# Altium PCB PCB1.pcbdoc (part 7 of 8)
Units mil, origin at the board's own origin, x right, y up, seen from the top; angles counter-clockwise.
Board outline 5129 x 4161 mil, 8 copper layers (Top Layer, GND1, 内层2, VCC, 内层4, Inner5, GND2, Bottom Layer); 498 components, 453 nets, 2574 pads, 1361 vias.

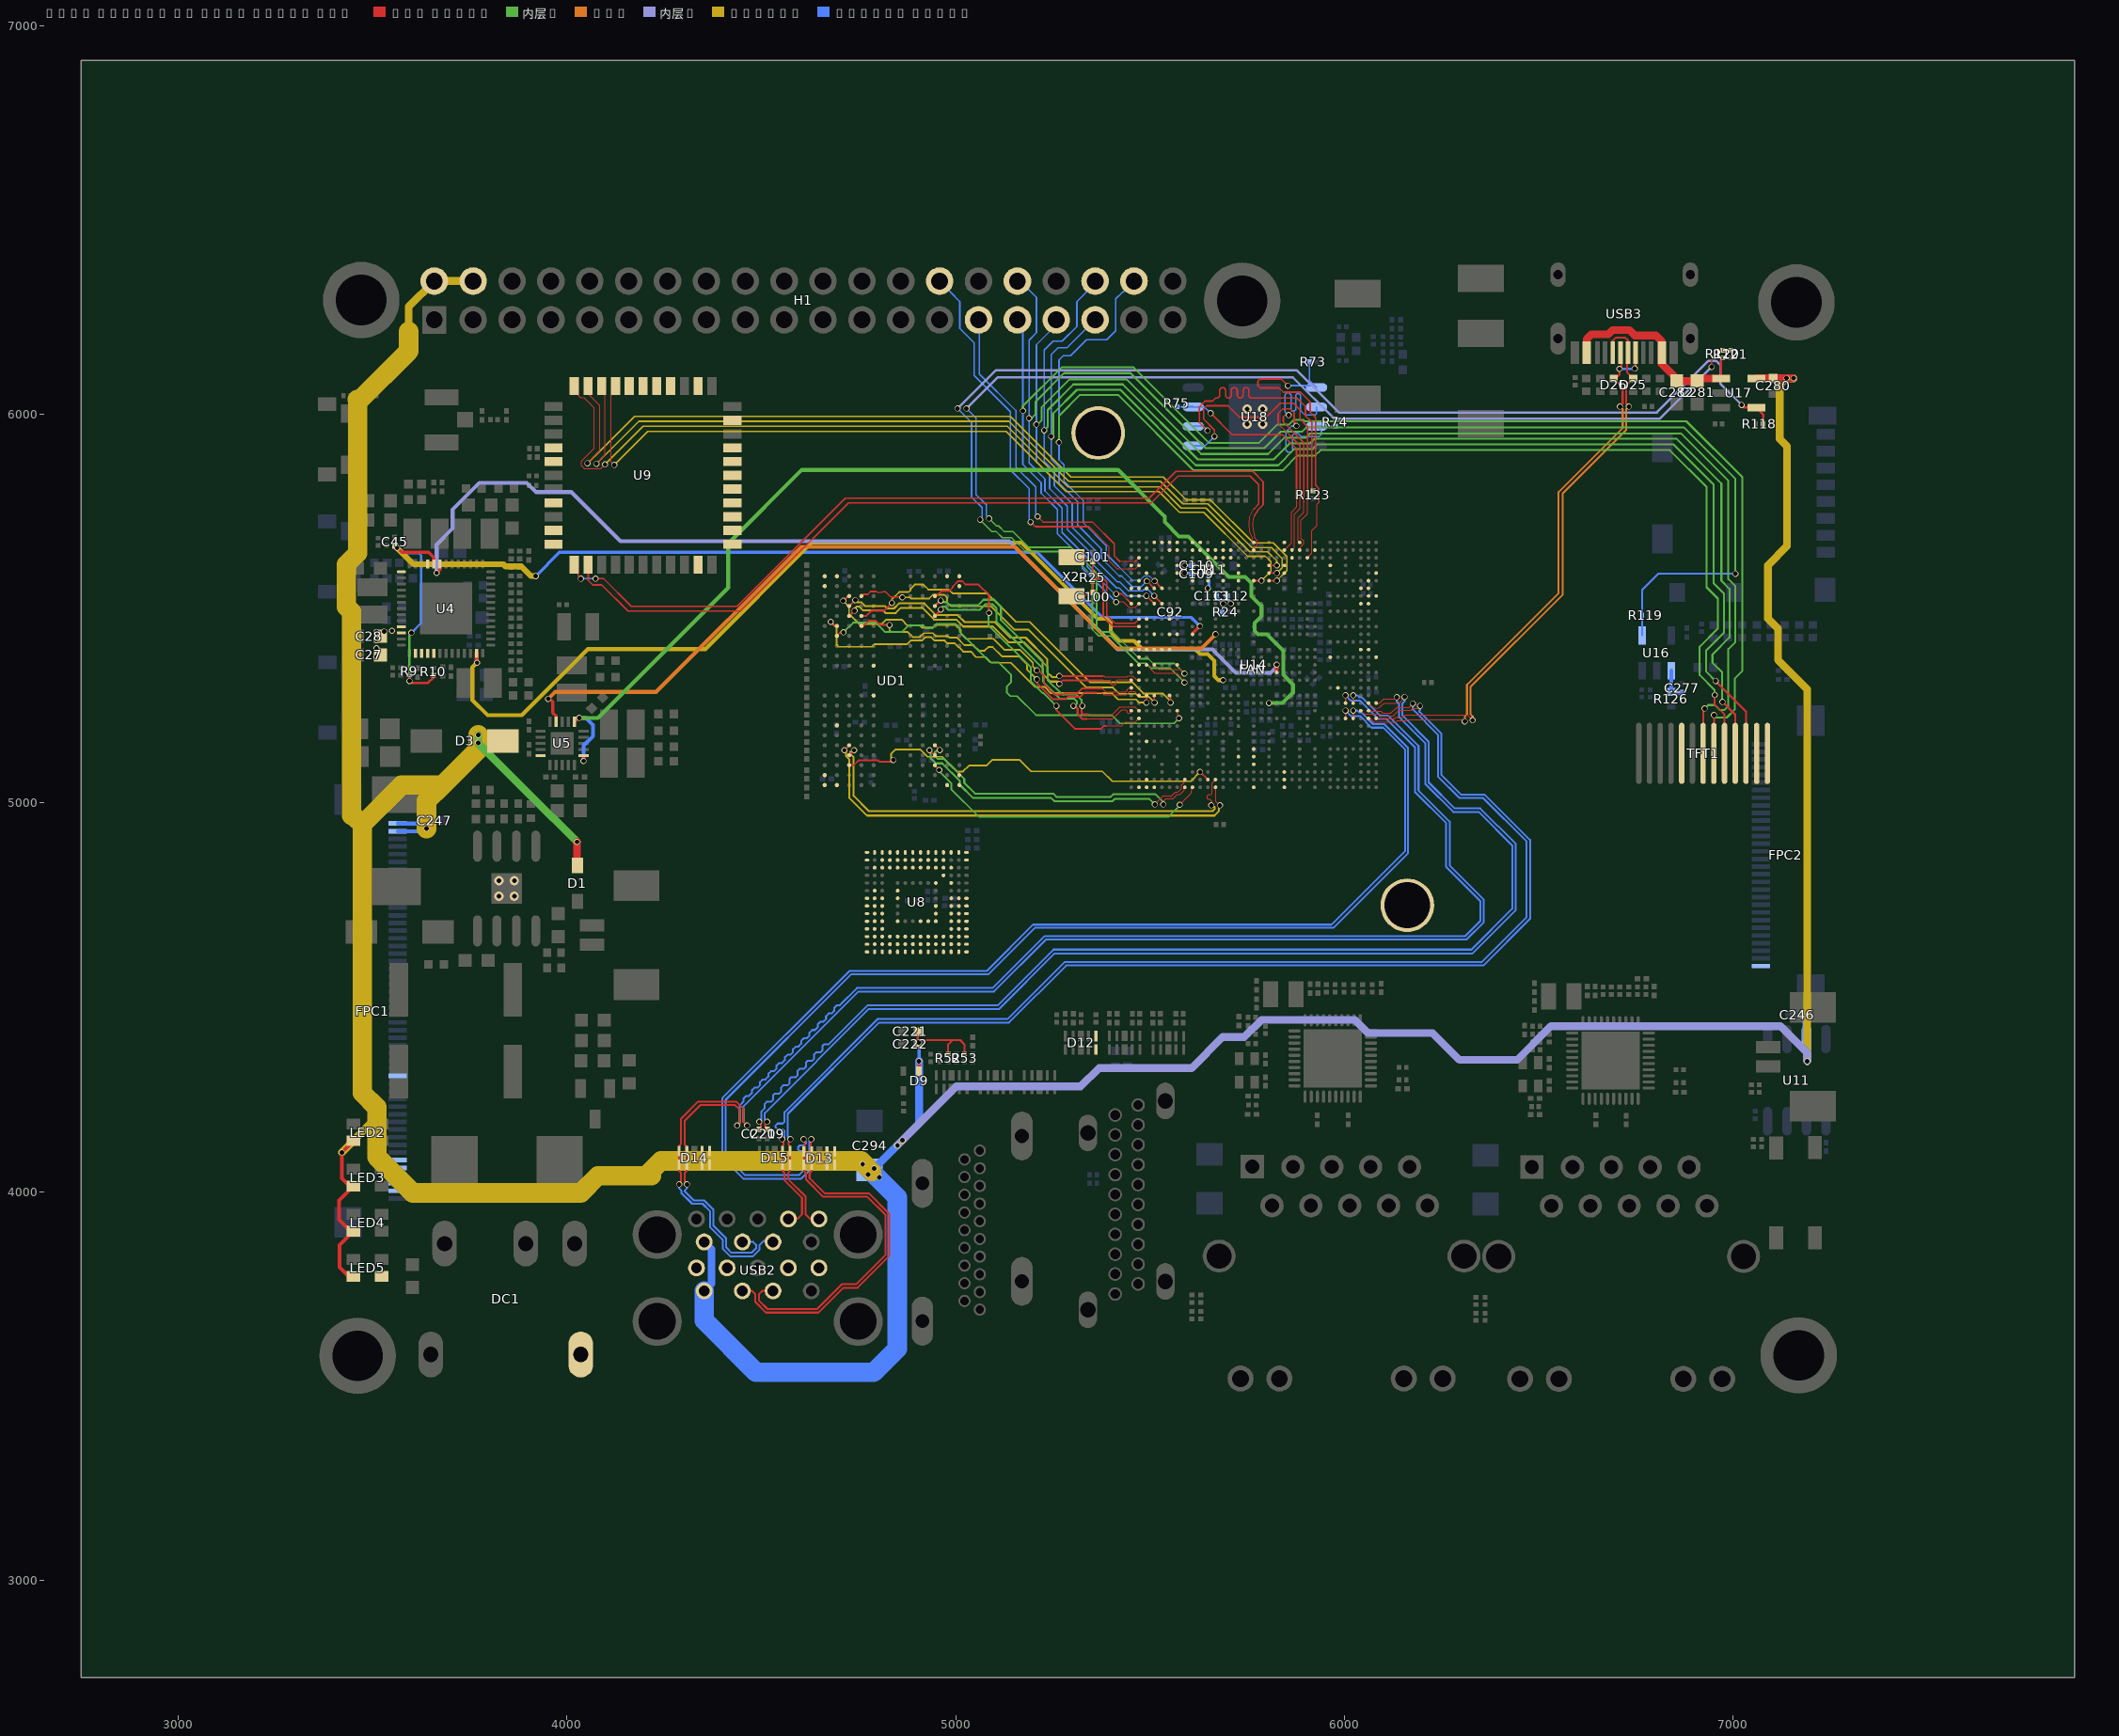
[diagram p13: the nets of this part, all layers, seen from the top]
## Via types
v1: diameter 15.7, hole 11.8, Top Layer to Bottom Layer, 570 vias
v2: diameter 15.75, hole 11.8, Top Layer to Bottom Layer, 504 vias
v3: diameter 15.75, hole 11.81, Top Layer to Bottom Layer, 279 vias
v4: diameter 24, hole 12, Top Layer to Bottom Layer, 8 vias

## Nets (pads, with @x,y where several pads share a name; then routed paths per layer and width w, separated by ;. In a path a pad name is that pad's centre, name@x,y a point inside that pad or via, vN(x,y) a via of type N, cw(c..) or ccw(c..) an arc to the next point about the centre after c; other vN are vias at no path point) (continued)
SDQ28: U14.AM21 UD1.U9 | length 856.7
  Top Layer w3: 5362.25,5283.97 5376.92,5283.97 5382.89,5278 5438.76,5278 5447.18,5286.42 5461.55,5286.42 U14.AM21@5471.37,5276.6
  Top Layer w4.5: UD1.U9@4757.66,5455.99 4763.94,5455.99 4776.92,5468.97 4794.92,5468.97 4805.92,5457.97 v3(4829.92,5457.97) ; v3(5209.02,5318.07) 5209.02,5308.87 5250.92,5266.97 5282.92,5266.97 5288.92,5272.97 5319.92,5272.97 5330.92,5283.97 5362.25,5283.97
  Inner5 w4.5: v3(4829.92,5457.97) 4829.92,5444.47 4834.42,5439.97 4876.92,5439.97 4889.92,5426.97 4907.92,5426.97 4917.92,5436.97 4941.92,5436.97 4949.92,5428.97 4980.92,5428.97 4983.92,5425.97 5002.92,5425.97 5022.92,5405.97 5045.6,5405.97 5059.6,5391.97 5074.92,5391.97 5083.92,5400.97 5095.58,5400.97 5119.08,5377.47 5162.42,5377.47 5183.92,5355.97 5183.92,5342.63 5208.48,5318.07 v3(5209.02,5318.07)
SDQ29: U14.AL21 UD1.U11 | length 983.1
  Top Layer w4.5: v3(4678.84,5465.97) 4688.82,5455.99 UD1.U11@4694.67,5455.99 ; v3(5491.05,5258.43) U14.AL21@5491.05,5276.59
  Inner5 w4.5: v3(4678.84,5465.97) 4693.92,5450.89 4693.92,5406.47 4698.42,5401.97 4784.92,5401.97 4791.92,5408.97 4875.92,5408.97 4884.92,5417.97 4913.97,5417.97 4923,5427 4936.89,5427 4945.92,5417.97 4971.92,5417.97 4978.92,5410.97 4997.92,5410.97 5019.42,5389.47 5038.76,5389.47 5052.76,5375.47 5077.42,5375.47 5091.92,5360.97 5141.92,5360.97 5203.91,5298.98 5228.91,5298.98 5245.42,5282.47 5402.42,5282.47 5418.42,5266.47 5464.42,5266.47 5472.46,5258.43 v3(5491.05,5258.43)
SDQ30: U14.AK21 UD1.Y9 | length 912.8
  Top Layer w4: UD1.Y9@4757.66,5532.76 4761.89,5537 4774,5537 4781,5544 4796,5544 4803,5541 4818.89,5544 4832.92,5529.97 4861.92,5529.97 v3(4862.92,5528.97) ; U14.AK21@5510.73,5276.59 5510.73,5259.57 v3(5511.96,5258.34)
  Inner5 w4.5: v3(4862.92,5528.97) 4881.92,5528.97 4884.92,5525.97 4931.92,5525.97 4941.92,5535.97 4970.92,5535.97 4977.92,5528.97 4977.92,5515.97 4987.92,5505.97 5091.53,5505.97 5151.53,5445.97 5187.56,5445.97 5336.56,5296.97 5404.92,5296.97 5420.92,5280.97 5463.92,5280.97 5471.89,5273 5497.3,5273 v3(5511.96,5258.34)
SDQ31: U14.AH21 UD1.V9 | length 979.8
  Top Layer w4.5: UD1.V9@4757.66,5481.58 4770.54,5481.58 4783.72,5494.76 4816.71,5494.76 4835.92,5513.97 v3(4835.92,5514.97) ; v3(5552.96,5258.34) U14.AH21@5552.96,5273.75
  Inner5 w4.5: v3(4835.92,5514.97) 4835.92,5523.97 4854.92,5542.97 4879.42,5542.97 4883.92,5547.47 4883.92,5550.97 4894.92,5561.97 4916.91,5561.97 4929.91,5548.97 4982.92,5548.97 4992.92,5538.97 5081.87,5538.97 5154.87,5465.97 5190.9,5465.97 5345.9,5310.97 5453.92,5310.97 5482.89,5282 5532.89,5282 5552.96,5261.93 v3(5552.96,5258.34)
SDQM0: U14.AE33 UD1.C3 | length 767.8
  Top Layer w3: v3(5576.61,4995.51) 5605.84,5024.74 5607.28,5033.54 U14.AE33@5608.9,5040.65
  Top Layer w4.5: UD1.C3@4946.64,5097.72 4957.92,5086.44 v3(4957.92,5084.97)
  内层2 w4.5: v3(4957.92,5084.97) 4957.92,5081.97 4988.92,5050.97 4988.92,5035.97 5060.17,4964.72 5547.65,4964.72 5576.44,4993.51 5576.44,4995.34 v3(5576.61,4995.51)
SDQM1: U14.AC32 UD1.C10 | length 1036.8
  Top Layer w4.5: UD1.C10@4726.16,5097.72 4738.67,5097.72 4750.92,5109.97 4800.92,5109.97 4804.92,5105.97 4834.92,5105.97 v3(4839.92,5110.97) ; v3(5628.92,5079.97) 5648.54,5060.35 U14.AC32@5648.54,5060.06
  Inner5 w4.5: v3(4839.92,5110.97) 4833.92,5116.97 4833.92,5125.97 4845.92,5137.97 4908.92,5137.97 4927.92,5118.97 4965.92,5118.97 5003.92,5080.97 5018.92,5080.97 5034.34,5096.39 5079.34,5096.39 5093.92,5110.97 5164.92,5110.97 5194.42,5081.47 5377.42,5081.47 5402.92,5055.97 5604.92,5055.97 v3(5628.92,5079.97)
SDQM2: U14.AM24 UD1.Y3 | length 785.1
  Top Layer w3: 5386.92,5197.97 5425.92,5197.97 5435.43,5207.49 5461.31,5207.49 U14.AM24@5471.37,5217.54
  Top Layer w4.5: UD1.Y3@4946.64,5532.76 4950.71,5532.76 4962.92,5544.97 4982.97,5544.97 4993,5555 4993,5557.45 5006.55,5571 5016.89,5571 5025.92,5561.97 5058.92,5561.97 5085.92,5534.97 v3(5085.92,5488.97) ; v3(5258.92,5249.97) 5258.92,5238.53 5306.48,5190.97 5373.92,5190.97 5380.92,5197.97 5386.92,5197.97
  内层2 w4.5: v3(5085.92,5488.97) 5084.92,5487.97 5084.92,5458.02 5086.92,5456.02 5086.92,5455.65 5193.92,5348.65 5193.92,5312.31 5223.26,5282.97 5225.92,5282.97 v3(5258.92,5249.97)
SDQM3: U14.AN20 UD1.Y10 | length 923.7
  Top Layer w3: 5376.92,5295.24 5386.16,5286 5437.15,5286 5447.44,5296.28 U14.AN20@5451.69,5296.28
  Top Layer w4.5: v3(4710.92,5519.97) 4723.71,5532.76 UD1.Y10@4726.16,5532.76 ; v3(5208.92,5340.97) 5212.92,5340.97 5227.92,5325.97 5227.92,5305.97 5254.92,5278.97 5276.92,5278.97 5279.92,5281.97 5312.92,5281.97 5326.19,5295.24 5376.92,5295.24
  Inner5 w4.5: v3(4710.92,5519.97) 4725.92,5504.97 4725.92,5486.97 4751.92,5460.97 4810.92,5460.97 4821.92,5471.97 4861.03,5471.97 4876.03,5456.97 4907.92,5456.97 4913.92,5450.97 4941.92,5450.97 4948.92,5457.97 4999.92,5457.97 5013.92,5443.97 5013.92,5435.97 5027.17,5422.72 5097.17,5422.72 5125.92,5393.97 5165.92,5393.97 5198.92,5360.97 5198.92,5350.97 v3(5208.92,5340.97)
SDQS0N: U14.AF33 UD1.E3 | length 777.5
  Top Layer w3: v3(5534.44,4996.51) 5534.44,5004.49 5539.92,5009.97 5558.17,5009.97 5569.17,5020.97 5576.24,5020.97 5587.66,5032.39 5587.66,5038.56 U14.AF33@5589.48,5040.38
  Top Layer w3.8: UD1.E3@4946.64,5148.9 v3(4959.44,5136.1)
  内层2 w5: v3(4959.44,5136.1) 4952.41,5136.08 4947.42,5131.05 4947.42,5120.5 4954.48,5113.47 4970.7,5113.47 5022.42,5061.75 5022.42,5051.74 5049.94,5024.22 5250.75,5024.22 5259,5015.97 5398.91,5015.97 5405.41,5022.47 5514.59,5022.47 5534.44,5002.62 v3(5534.44,4996.51)
SDQS0P: U14.AF32 UD1.D3 | length 789.5
  Top Layer w3: v3(5512.44,4996.51) 5532.92,5017 5555,5017 5566,5028 5571.94,5028 5579.92,5035.97 5579.92,5044.97 5589.48,5054.53 U14.AF32@5589.48,5060.06
  Top Layer w5: v3(4932.92,5135.97) 4945.58,5123.31 UD1.D3@4946.64,5123.31
  内层2 w5: v3(4932.92,5135.97) 4935.89,5133.02 4935.92,5115.72 4949.73,5101.97 4965.93,5101.97 5010.92,5056.98 5010.92,5046.97 5045.17,5012.72 5245.98,5012.72 5254.23,5004.47 5403.68,5004.47 5410.18,5010.97 5497.98,5010.97 v3(5512.44,4996.51)
SDQS1N: U14.AB33 UD1.E10 | length 1187.6
  Top Layer w3: U14.AB33@5668.22,5040.38 5668.22,5005.67 v3(5679.92,4993.97)
  Top Layer w5: v3(4713.92,5135.97) 4726.16,5148.21 UD1.E10@4726.16,5148.9
  Inner5 w5: v3(4713.92,5135.97) 4713.92,5135.85 4717.9,5131.87 4717.9,5120.99 4726.42,5112.47 4726.42,5013.47 4772.17,4967.72 5666.18,4967.72 5677.92,4979.46 5677.92,4991.97 v3(5679.92,4993.97)
SDQS1P: U14.AB32 UD1.D10 | length 1194.4
  Top Layer w3: v3(5657.92,4993.97) 5657.92,4998.97 5658.42,4999.47 5658.42,5005.66 5655.42,5008.66 5650.06,5008.66 5646.18,5012.54 5646.18,5016.79 5650.05,5020.66 5655.42,5020.66 5658.42,5023.66 ; 5658.6,5023.82 5658.7,5036.87 5658.36,5050.2 U14.AB32@5668.22,5060.06
  Top Layer w5: UD1.D10@4726.26,5123.31 v3(4738.92,5135.97)
  Inner5 w5: v3(4738.92,5135.97) 4734.42,5135.97 4729.4,5130.95 4729.4,5125.76 4737.92,5117.24 4737.92,5018.24 4776.94,4979.22 5661.41,4979.22 5666.42,4984.23 5666.42,4988.97 5661.42,4993.97 v3(5657.92,4993.97)
SDQS2N: U14.AN23 UD1.V3 | length 741.1
  Top Layer w3: 5337.29,5216.04 5402.98,5216.03 5426.04,5239.09 5438.43,5239.09 5441.43,5236.09 5441.43,5232.72 5444.44,5229.71 5448.68,5229.71 5451.69,5232.72 U14.AN23@5451.69,5237.23
  Top Layer w5: UD1.V3@4946.64,5481.58 4961.92,5496.86 v3(4961.92,5497.97) ; v3(5302.92,5249.97) 5306.92,5249.97 5313.92,5242.97 5313.92,5228.82 5326.7,5216.04 5337.29,5216.04
  内层2 w5: v3(4961.92,5497.97) 4961.92,5500.47 4966.92,5505.47 4973.15,5505.47 4981.65,5496.97 5061.91,5496.97 5076.41,5511.47 5094.43,5511.47 5105.17,5500.73 5105.17,5465.71 5225.42,5345.46 5225.42,5311.41 5268.86,5267.97 5305.41,5267.97 5312.42,5260.96 5312.42,5255.47 5306.92,5249.97 v3(5302.92,5249.97)
SDQS2P: U14.AM23 UD1.W3 | length 740.4
  Top Layer w3: 5339.59,5228.05 5343.84,5228.05 5347.86,5224.03 5399.66,5224.03 5422.72,5247.09 5461.55,5247.05 U14.AM23@5471.37,5237.23
  Top Layer w5: UD1.W3@4946.64,5507.17 4960.05,5520.58 4961.53,5520.58 v3(4961.92,5520.97) ; v3(5325.92,5249.97) 5323.92,5247.97 5323.92,5232.97 5328.92,5227.97 5339.51,5227.97 5339.59,5228.05
  内层2 w5: v3(4961.92,5520.97) 4965.92,5516.97 4977.92,5516.97 4986.42,5508.47 5057.14,5508.47 5071.64,5522.97 5099.2,5522.97 5116.67,5505.5 5116.67,5470.48 5236.92,5350.23 5236.92,5316.18 5273.63,5279.47 5310.18,5279.47 5323.92,5265.73 5323.92,5251.97 v3(5325.92,5249.97)
SDQS3N: U14.AN19 UD1.V10 | length 873.1
  Top Layer w3: 5378.21,5315.99 5396.95,5315.97 5399.95,5312.97 5399.95,5306.23 5402.95,5303.23 5408.94,5303.23 5411.95,5306.24 5411.95,5312.97 5414.95,5315.97 U14.AN19@5451.69,5315.97
  Top Layer w5: UD1.V10@4726.16,5481.58 4726.53,5481.58 v3(4739.92,5494.97) ; v3(5267.17,5306.46) 5276.7,5315.99 5378.21,5315.99
  Inner5 w5: v3(4739.92,5494.97) 4739.92,5499.97 4744.92,5504.97 4752.65,5504.97 4762.15,5495.47 4813.16,5495.47 4819.66,5488.97 4846.19,5488.97 4859.19,5501.97 4914.93,5501.97 4944.93,5471.97 5001.92,5471.97 5019.92,5453.97 5095.92,5453.97 5135.92,5413.97 5175.35,5413.97 5223.92,5365.4 5223.92,5331.98 5243.43,5312.47 5260.64,5312.47 5266.65,5306.46 v3(5267.17,5306.46)
SDQS3P: U14.AM19 UD1.W10 | length 870.7
  Top Layer w3: 5378.21,5325.99 5382.36,5325.99 5384.36,5323.99 5440.54,5323.97 5442.36,5325.79 5457.11,5325.79 5466.93,5315.97 U14.AM19@5471.37,5315.97
  Top Layer w5: UD1.W10@4726.16,5507.17 4727.12,5507.17 v3(4741.92,5521.97) ; v3(5266.92,5326.65) 5267.58,5325.99 5378.21,5325.99
  Inner5 w5: v3(4741.92,5521.97) 4747.42,5516.47 4757.42,5516.47 4766.92,5506.97 4817.93,5506.97 4824.43,5500.47 4841.42,5500.47 4854.42,5513.47 4919.7,5513.47 4949.7,5483.47 5005.53,5483.47 5023.53,5465.47 5100.69,5465.47 5140.69,5425.47 5180.12,5425.47 5235.42,5370.17 5235.42,5336.75 5248.2,5323.97 5264.24,5323.97 v3(5266.92,5326.65)
SPI0-CLK: R123.1 U18.6 | length 751.8
  Top Layer w4: v2(5648,5958) 5627,5979 5627,6019 5642,6034 5661,6034 5669,6042 5672.06,6042 ccw(c5672.06,6049.5) 5679.56,6049.5 5679.56,6061.5 cw(c5687.06,6061.5) 5694.56,6061.5 5694.56,6049.5 ccw(c5702.06,6049.5) 5709.56,6049.5 5709.56,6061.5 cw(c5717.06,6061.5) 5724.56,6061.5 5724.56,6049.5 ccw(c5732.06,6049.5) 5739.56,6049.5 5739.56,6061.5 cw(c5747.06,6061.5) 5754.56,6061.5 5754.56,6049.5 ccw(c5762.06,6049.5) 5762.06,6042 5878,6042 5900,6020 5900,5996 5916,5980 5916,5806.51 R123.1@5920,5802.51
  Bottom Layer w4: U18.6@5611.23,5969 5637,5969 v2(5648,5958)
SPI0-CS: R73.1 U14.K3 U18.1 | length 814.8
  Top Layer w3: U14.K3@5904.69,5631.01 5914.96,5641.28 5914.96,5699.52 5928.04,5712.6 5928.04,5767.86 5934,5773.83 5934,5779
  Top Layer w4: v2(5855,6074) 5838,6091 5783,6091 5777.83,6085.83 5777.83,6073.17 5783,6068 5832,6068 5843,6057 5887,6057 5912,6032 5912,6006 5926,5992 5926,5818 5934,5810 5934,5779
  Bottom Layer w4: v2(5855,6074) U18.1@5923.77,6074 ; R73.1@5910.49,6135 5910.49,6087.28 U18.1@5923.77,6074 ; U18.1@5928.77,6069 U18.1@5923.77,6074
SPI0-HOLD: R75.1 U14.N2 U18.7 | length 626.3
  Top Layer w3: U14.N2@5845.59,5650.71 5862.87,5667.99 5862.87,5747.04 5877,5761.17 5877,5782.3
  Top Layer w4: v2(5656,6003) 5711,5948 5840.04,5948 5877,5911.04 5877,5782.3
  Bottom Layer w4: R75.1@5569,6019.49 5610.74,6019.49 5611.23,6019 5640,6019 v2(5656,6003)
SPI0-MISO: U14.L1 U18.2 | length 657.2
  Top Layer w3: U14.L1@5884.97,5670.43 5881.01,5674.39 5881,5733 5895.89,5747.89 ; 5896,5747.89 5896,5775
  Top Layer w4: v2(5857,5998) 5847,5998 5843,5994 5843,5980 5896,5927 5896,5775
  Bottom Layer w4: v2(5857,5998) 5856,5998 5847,6007 5847,6050 5852,6055 5858,6055 5863,6050 5863,6011.76 5866.1,6008.66 5871.66,6008.66 5875,6012 5875,6050 5878.5,6053.5 5883.5,6053.5 5887,6050 5887,6010 5899,5998 5925,5998 5928.77,6001.77 U18.2@5928.77,6019
SPI0-MOSI: U14.L2 U18.5 | length 815.6
  Top Layer w3: U14.L2@5884.96,5650.74 5884.96,5656.51 5895.2,5666.75 5895.2,5674.08 5889,5680.16 5889,5728 5905.5,5744.5 5905.5,5777
  Top Layer w4: v2(5666,5943) 5666,5960 5638,5988 5638,6014 5646,6022 5701,6022 5730,5993 5799,5993 5835,6029 5869,6029 5886,6012 5886,5988 5905.5,5968.5 5905.5,5777
  Bottom Layer w4: U18.5@5611.23,5919 5642,5919 v2(5666,5943)
SPI0-WP: R74.1 U14.M2 U18.3 | length 766.8
  Top Layer w3: U14.M2@5865.29,5650.71 5871.43,5656.85 5871.43,5743.25 5886.2,5758.02 5886.2,5782
  Top Layer w4: v2(5877,5970) 5871,5976 5871,6004 5861,6014 5842,6014 5830,6002 5830,5976 5886.2,5919.8 5886.2,5782
  Bottom Layer w4: v2(5877,5970) 5865,5970 5850,5955 5850,5908 5855,5903 5862.77,5903 5867,5907.23 5867,5947 5872,5952 5880,5952 5889,5943 5935,5943 5941,5949 5941,5956.77 5928.77,5969 5975.51,5969 R74.1@5977,5970.49
SPI-LCD-BLK: H1.32 R119.2 U14.AN9 U16.4 | length 3640.4
  Top Layer w4: v1(5413,5538) 5426.96,5538 U14.AN9@5452.01,5512.95
  内层2 w5: v1(5189,5990) 5195,5990 5206,6001 5206,6033 5279,6106 5450,6106 5643,5913 5794,5913 5836,5955 5891,5955 5902,5966 6874,5966 7006,5834 v1(7006,5590)
  Bottom Layer w4: H1.32@5159,6343 5166,6343 5208,6301 5208,6210 5189,6191 v1(5189,5990) 5189,5875 5230,5834 5230,5803 5274,5759 5274,5696 5338,5632 5338,5609 5409,5538 v1(5413,5538)
  Bottom Layer w5: U16.4@6766.11,5431.15 6766.11,5548.11 6808,5590 v1(7006,5590)
SPI-LCD-CLK: H1.36 TFT1.4 U14.AJ9 | length 3771.4
  Top Layer w4: v2(5511,5533) 5511,5532.71 U14.AJ9@5530.76,5512.95
  Top Layer w5: v1(6973,5260) 7005.68,5227.32 TFT1.4@7005.68,5127.67
  内层2 w5: v1(5228,5959) 5237,5968 5237,6011 5303,6077 5430,6077 5623,5884 5818,5884 5859,5925 5911,5925 5923,5937 6855,5937 6970,5822 6970,5572 6991,5551 6991,5426 6947,5382 6947,5361 6972,5336 6972,5261 v1(6973,5260)
  Bottom Layer w4: H1.36@5359,6343 5359,6337 5312,6290 5312,6226 5274,6188 5251,6188 5228,6165 v1(5228,5959) 5228,5879 5254,5853 5254,5816 5300,5770 5300,5709 5363,5646 5363,5622 5416,5569 5422,5569 5445,5546 5481,5546 5484,5549 5495,5549 v2(5511,5533)
SPI-LCD-CS: H1.33 TFT1.7 U14.AK9 | length 3695.6
  Top Layer w4: v2(5491,5533) U14.AK9@5511.07,5512.95
  Top Layer w5: TFT1.7@6923,5127.67 6923,5239 v1(6927,5243)
  内层2 w5: v1(5208,5974) 5211,5974 5221,5984 5221,6018 5293,6090 5440,6090 5632,5898 5804,5898 5846,5940 5901,5940 5912,5951 6866,5951 6988,5829 6988,5576 7006,5558 7006,5414 6988,5396 6988,5250 6977,5239 6966,5239 6953,5252 6936,5252 v1(6927,5243)
  Bottom Layer w4: H1.33@5259,6243 5259,6230.05 5208,6179.05 v1(5208,5974) 5208,5877 5242,5843 5242,5809 5287,5764 5287,5704 5351,5640 5351,5616 5414,5553 5421,5553 5441,5533 v2(5491,5533)
SPI-LCD-DC: H1.38 TFT1.5 U14.AJ7 | length 3704.7
  Top Layer w4: v2@5512.08,5571 U14.AJ7@5530.76,5552.32
  Top Layer w5: v1(6953,5278) 6953,5253 6978.12,5227.88 TFT1.5@6978.12,5127.67
  内层2 w5: v1(5266,5928) 5266,5996 5320,6050 5418,6050 5612,5856 5841,5856 5879,5894 5925,5894 5939,5908 6837,5908 6932,5813 6932,5555 6961,5526 6961,5449 6914,5402 6914,5329 6953,5290 v1(6953,5278)
  Bottom Layer w3: 5455,5573 5474,5573 5485,5584 5499,5584 v2(5512,5571)
  Bottom Layer w4: 5455,5573 5388,5640 5388,5662 5328,5722 5328,5779 5279,5828 5279,5870 5266,5883 v1(5266,5928) 5266,6140 5277,6151 5296,6151 5337,6192 5389,6192 5412,6215 5412,6297 5429.91,6314.91 5430.91,6314.91 H1.38@5459,6343
SPI-LCD-MOSI: H1.35 TFT1.3 U14.AK7 | length 3602.2
  Top Layer w4: v2(5492,5571) 5492.39,5571 U14.AK7@5511.07,5552.32
  Top Layer w5: v1(6955,5314) 7033.24,5235.76 TFT1.3@7033.24,5127.67
  内层2 w5: v1(5246,5943) 5251,5948 5251,6002 5312,6063 5424,6063 5618,5869 5830,5869 5872,5911 5919,5911 5931,5923 6846,5923 6950,5819 6950,5565 6977,5538 6977,5439 6931,5393 6931,5338 v1(6955,5314)
  Bottom Layer w4: H1.35@5359,6243 5358,6243 5286,6171 5263,6171 5246,6154 v1(5246,5943) 5246,5884 5266,5864 5266,5823 5314,5775 5314,5715 5375,5654 5375,5630 5421,5584 5427,5584 5454,5557 5478,5557 v2(5492,5571)
SPI-LCD-RST: H1.31 TFT1.6 U14.AM9 | length 3739.7
  Top Layer w3: v2(5413,5517) 5433,5517 5447,5503 5461.75,5503 U14.AM9@5471.7,5512.95
  Top Layer w5: TFT1.6@6950.56,5127.67 6951,5128.11 v1(6951,5226)
  内层2 w5: v1(5173,6009) 5173,6021 5273,6121 5458,6121 5653,5926 5780,5926 5828,5974 5858,5974 5870,5986 5894,5986 5898,5982 6880,5982 7024,5838 7024,5340 7004,5320 7004,5240 6984,5220 6957,5220 v1(6951,5226)
  Bottom Layer w4: H1.31@5159,6243 5173,6229 v1(5173,6009) 5173,5871 5220,5824 5220,5797 5262,5755 5262,5693 5326,5629 5326,5604 v2(5413,5517)
SRST: U14.AG23 UD1.T11 | length 1097.6
  Top Layer w3: U14.AG23@5569.8,5237.23 5569.79,5226.35 5573.83,5222.31 5573.83,5218.95 v3(5574.61,5218.18)
  Top Layer w4: UD1.T11@4694.67,5430.4 4702.25,5437.98 4709.93,5437.98 4710.44,5438.49 4710.92,5438.49 v3(4711.4,5438.97)
  内层2 w4.5: v3(4711.4,5438.97) 4736.4,5463.97 4794.92,5463.97 4818.92,5439.97 4861.92,5439.97 4878.92,5456.97 4916.92,5456.97 4922.92,5450.97 4940.92,5450.97 4950.92,5460.97 4998.92,5460.97 5010.92,5448.97 5010.92,5439.97 5088.92,5361.97 5110.58,5361.97 5142.92,5329.63 5142.92,5310.97 5131.92,5299.97 5131.92,5283.99 5140.94,5274.97 5157.92,5274.97 5206.92,5225.97 5401.92,5225.97 5422.92,5204.97 5561.4,5204.97 v3(5574.61,5218.18)
STWI1-SCK: H1.28 U14.AM4 | length 1086
  Top Layer w3: 5366,5688 5395,5659 5395,5623 5416.43,5601.57 5461.63,5601.57 U14.AM4@5470.98,5610.92
  Top Layer w4: v1(5193,5723) 5205,5711 5343,5711 5366,5688
  Bottom Layer w4: H1.28@4959,6343 4998.26,6303.74 4998.26,6302.74 ; 4987.09,6313.91 4998.26,6302.74 ; v1(5193,5723) 5189,5727 5189,5809 5141,5857 5141,6007 5048,6100 5048,6184 5011,6221 5011,6290 4998.26,6302.74
STWI1-SDA: H1.29 U14.AM3 | length 900
  Top Layer w3: 5423,5621 5461.64,5621
  Top Layer w4: v1(5211,5737) 5225,5723 5352,5723 5408,5667 5408,5636 5423,5621 ; 5461.64,5621 U14.AM3@5471.7,5631.06
  Bottom Layer w4: H1.29@5059,6243 5061,6241 5061,6104 5155,6010 5155,5864 5206,5813 5206,5742 v1(5211,5737)
UART1-CTS: U9.41 U14.U6 | length 2154.1
  Top Layer w3: v2(4122,5870) 4113,5879 4113,6048 4125.13,6060.13 U9.41@4125.13,6073.06
  Top Layer w4: U14.U6@5766.98,5572.01 v2(5786.98,5572.01)
  Inner5 w4: v2(4122,5870) 4208,5956 5130,5956 5285,5801 5523,5801 5576,5748 5638,5748 5751,5635 5797,5635 5811,5621 5811,5596.03 v2(5786.98,5572.01)
UART1-RTS: U9.44 U14.R4 | length 2257.5
  Top Layer w3: U9.44@4018.84,6073.06 4018.84,6060.16 4037,6042 4045,6042 4070,6017 4070,5912 4037.41,5879.41 4037.41,5867.8 4046.21,5859 4086,5859 v2(4098,5871)
  Top Layer w4: U14.R4@5806.34,5611.38 v2(5826.34,5611.38)
  Inner5 w4: v2(4098,5871) 4196,5969 5133,5969 5289,5813 5526,5813 5580,5759 5644,5759 5757,5646 5803,5646 5826.34,5622.66 v2(5826.34,5611.38)
UART1-RX: U9.42 U14.R5 | length 2230.9
  Top Layer w3: v2(4076,5873) 4098,5895 4098,6064.76 U9.42@4089.7,6073.06
  Top Layer w4: U14.R5@5806.35,5591.69 v2(5826.35,5591.69)
  Inner5 w4: v2(4076,5873) 4185,5982 5137,5982 5291,5828 5527,5828 5585,5770 5649,5770 5762,5657 5812,5657 5840,5629 5840,5605.33 v2(5826.35,5591.69)
UART1-TX: U9.43 U14.R6 | length 2316.3
  Top Layer w3: v2(4053,5874) 4085,5906 4085,6022 4054.27,6052.73 U9.43@4054.27,6073.06
  Top Layer w4: U14.R6@5806.35,5572.01 v2(5826.35,5572.01)
  Inner5 w4: v2(4053,5874) 4174,5995 5141,5995 5297,5839 5534,5839 5593,5780 5655,5780 5766,5669 5817,5669 5852,5634 5852,5597.66 v2(5826.35,5572.01)
  other v2: 4053,5874
USB0-DM: D26.2 U14.B24 USB3.A7 USB3.B7 | length 1482.6
  Top Layer w3: U14.B24@6062.26,5217.68 6066.5,5217.68 6076.01,5208.17 6132.17,5208.17 6136,5212 6158,5212 6161,5215 6305,5215 v2(6310,5210)
  Top Layer w5: v2(6709,6020) 6716,6027 6716,6069.4 D26.2@6693,6092.4 6698.4,6092.4 6708,6102 v2(6708,6117) 6713,6122 6713,6155.86 USB3.A7@6710.16,6158.7 ; v2(6747,6118) 6749.53,6120.53 USB3.B7@6749.53,6158.7
  VCC w5: v2(6310,5210) 6310,5223.37 6315.5,5228.87 6315.5,5304.23 6551,5539.73 6551,5800 6716,5965 6716,6013 v2(6709,6020)
  Bottom Layer w5: v2(6708,6117) 6746,6117 v2(6747,6118)
USB0-DP: D25.2 U14.A24 USB3.A6 USB3.B6 | length 1500.2
  Top Layer w3: U14.A24@6081.94,5217.67 6090.33,5217.67 6092,5216 6128,5216 6131,5219 6150,5219 6156.37,5225.37 6317.63,5225.37 v2(6330,5213)
  Top Layer w5: USB3.B6@6690.47,6158.7 6690.47,6189.47 6698,6197 6723,6197 6729.84,6190.16 USB3.A6@6729.84,6158.7 6727,6155.86 6727,6108.4 D25.2@6743,6092.4 6725,6074.4 6725,6027 v2(6732,6020)
  VCC w5: v2(6330,5213) 6330,5223.37 6324.5,5228.87 6324.5,5298.5 6562,5536 6562,5797 6725,5960 6725,6013 v2(6732,6020)
USB0-DRVVBUS: R118.2 U14.AL17 U17.4 | length 3542.1
  Top Layer w3: U14.AL17@5491.39,5355.47 5513.86,5333 5570.83,5333 5579,5323 5587,5319 v1(5589,5310) v1@5589,5314.83
  Top Layer w6: v1(7022,6024) 7028.38,6017.62 U17.4@7059.88,6017.62 7077.28,6000.22 R118.2@7077.28,5975.2
  内层2 w4: v1(5063,5729) 5094,5698 5105,5698 5120,5683 5144,5683 5180,5647 5289,5647 5352,5584 5352,5446 5368,5430 5400,5430 5470,5360 5490,5360 5503,5347 5552,5347 v1(5589,5310)
  内层4 w6: v1(5005,6015) 5103,6113 5878,6113 5986,6005 6804,6005 6937,6138 6956,6138 6968,6126 6968,6078 v1(7022,6024)
  Bottom Layer w4: v1(5005,6015) 5041,5979 5041,5787 5068,5760 5068,5734 v1(5063,5729)
USB0-VBUSDET: R120.1 R121.2 U14.AK17 | length 3270.8
  Top Layer w3: U14.AK17@5511.06,5355.47 5523.53,5343 5579,5343 v1(5589,5333)
  Top Layer w4: v2(6945,6122) 6945,6140.49 6950.23,6145.72 R120.1@6973.23,6164.74 R121.2@6994,6164.51
  内层2 w4: v1(5086,5732) 5105,5713 5111,5713 5126,5698 5148,5698 5188,5658 5297,5658 5363,5592 5363,5451 5374,5440 5404,5440 5473,5371 5496,5371 5508,5359 5563,5359 v1(5589,5333)
  内层4 w6: v1(5028,6015) 5108,6095 5868,6095 5974,5989 6812,5989 v2(6945,6122)
  Bottom Layer w4: v1(5028,6015) 5053,5990 5053,5793 5079,5767 5079,5739 v1(5086,5732)
USB1-DM: D13.4 D13.7 U14.E24 USB2.2 | length 3914.8
  Top Layer w4: U14.E24@6003.2,5217.67 v2(6003.2,5237.67)
  Top Layer w5: USB2.2@4451.63,3744.85 4476.13,3744.85 4484.98,3736 4484.98,3716.27 4512.25,3689 4647,3689 4710.98,3752.98 4747.73,3752.98 4829.02,3834.27 4829.02,3943.73 4776.75,3996 4663.37,3996 4624.37,4035 4624.37,4047.8 4629.7,4053.12 D13.7@4629.7,4069.01 D13.4@4629.7,4103.67 4627,4106.37 4627,4133 v2(4629,4135)
  Bottom Layer w5: v2(4629,4135) 4624,4130 4624,4055 4602,4033 4454.77,4033 4399.5,4088.27 4399.5,4240.23 4727.27,4568 5080.27,4568 5199.27,4687 5967,4687 6156,4876 6156,5138 6100,5194 6070.44,5194 6040.64,5223.79 6017.07,5223.79 v2(6003.2,5237.67)
USB1-DP: D13.5 D13.6 U14.D24 USB2.3 | length 3905.1
  Top Layer w4: U14.D24@6022.9,5217.67 v2(6022.9,5237.67)
  Top Layer w5: USB2.3@4530.37,3744.85 4502.85,3744.85 4494,3736 4494,3720 4515.98,3698.02 4643.29,3698.02 4707.27,3762 4744,3762 4820,3838 4820,3940 4773.02,3986.98 4659.64,3986.98 4615.36,4031.27 4615.36,4047.8 4610.03,4053.12 D13.6@4610.03,4069.01 D13.5@4610.03,4103.66 4612,4105.63 4612,4132 v2(4609,4135)
  Bottom Layer w5: v2(4609,4135) 4615,4129 4615,4124.24 4610,4119.24 4599.6,4119.24 4594.6,4114.24 4594.6,4109.24 4599.6,4104.24 4610,4104.24 4615,4099.24 4615,4094.24 4610,4089.24 4599.6,4089.24 4594.6,4084.24 4594.6,4079.24 4599.6,4074.24 4610,4074.24 4615,4069.24 4615,4060 4598,4043 4457.5,4043 4408.5,4092 4408.5,4236.5 4731,4559 5084,4559 5204,4679 5971.73,4679 6164,4871.27 6164,5141.31 6102.31,5203 6074.17,5203 6044.37,5232.79 6038.14,5232.79 6033.27,5237.67 v2(6022.9,5237.67)
USB2-DM: D14.4 D14.7 U14.E22 USB2.11 | length 3712.4
  Top Layer w4: U14.E22@6003.2,5257.04 v2(6003.2,5277.04)
  Top Layer w5: v2(4309,4019) 4302.97,4025.03 4302.97,4048.46 4308.3,4053.78 D14.7@4308.3,4069.67 D14.4@4308.3,4104.33 4308.3,4116.7 4303,4122 4303,4182 4344,4223 4432,4223 4445,4210 4445,4177 v2(4438,4170)
  Bottom Layer w5: v2(4309,4019) 4309,4008.63 4303.51,4003.13 4303.51,4000.63 4326.14,3978 4352.73,3978 4377.02,3953.72 4377.02,3912.98 4409.64,3880.36 4409.64,3857.11 4423.75,3843 4475,3843 4487,3855 4487,3863 4479.17,3870.83 USB2.11@4451.63,3870.83 ; v2(4438,4170) 4445,4177 4445,4222.73 4454.48,4232.21 4454.48,4239.28 4461.55,4246.35 4468.62,4246.35 4475.69,4253.42 4475.69,4260.49 4482.76,4267.56 4489.84,4267.56 4496.91,4274.63 4496.91,4281.71 4503.98,4288.78 4511.05,4288.78 4518.12,4295.85 4518.12,4302.92 4525.19,4309.99 4532.26,4309.99 4539.33,4317.06 4539.33,4324.13 4546.4,4331.2 4553.48,4331.2 4560.55,4338.27 4560.55,4345.35 4567.62,4352.42 4574.69,4352.42 4581.76,4359.49 4581.76,4366.56 4588.83,4373.63 4595.9,4373.63 4602.97,4380.7 4602.97,4387.77 4610.04,4394.84 4617.11,4394.84 4624.19,4401.91 4624.19,4408.98 4631.26,4416.06 4638.33,4416.06 4645.4,4423.13 4645.4,4430.2 4652.47,4437.27 4659.54,4437.27 4666.61,4444.34 4666.61,4451.41 4673.68,4458.48 4680.75,4458.48 4687.83,4465.55 4687.83,4472.62 4694.9,4479.7 4701.97,4479.7 4746.27,4524 5095.27,4524 5228.27,4657 6310,4657 6350,4697 6350,4747.27 6262,4835.27 6262,4948.27 6182,5028.27 6182,5143 6109,5216 6087.81,5216 6040.64,5263.17 6017.07,5263.17 v2(6003.2,5277.04)
USB2-DP: D14.5 D14.6 U14.D22 USB2.12 | length 3718
  Top Layer w4: U14.D22@6022.9,5257.04 v2(6022.9,5277.04)
  Top Layer w5: v2(4289,4019) 4293.96,4023.96 4293.96,4048.46 4288.63,4053.78 D14.6@4288.63,4069.67 D14.5@4288.63,4104.32 4288.63,4117.63 4294,4123 4294,4188 4338,4232 4435.73,4232 4454,4213.73 4454,4180 v2(4464,4170)
  Bottom Layer w5: v2(4289,4019) 4289,4008.63 4294.49,4003.13 4294.49,3996.9 4322.41,3968.98 4349,3968.98 4368,3949.98 4368,3909.25 4400.62,3876.62 4400.62,3853.38 4420.02,3833.98 4478.73,3833.98 4496.02,3851.27 4496.02,3863.02 4506,3873 4528.2,3873 USB2.12@4530.37,3870.83 ; v2(4464,4170) 4454,4180 4454,4219 4750,4515 5099,4515 5233,4649 6314.73,4649 6359,4693.27 6359,4751 6271,4839 6271,4952 6191,5032 6191,5146.73 6112.73,5225 6091.54,5225 6044.37,5272.17 6038.14,5272.17 6033.27,5277.04 v2(6022.9,5277.04)
USB2-RXN: D15.1 D15.10 U14.C23 USB2.14 | length 3314.7
  Top Layer w3: U14.C23@6042.58,5237.36 6052.54,5227.4 6092.6,5227.4 6096.76,5223.24 6124.24,5223.24 6138.36,5237.36 6170.36,5237.36 6175,5242 6187,5242 v2(6195,5250)
  Top Layer w5: v2(4575,4135) 4570,4130 4570,4121 4574.37,4116.63 D15.1@4574.37,4104.33 D15.10@4574.37,4069.67 4574.37,4053.78 4569.04,4048.46 4569.04,4032.96 4614.02,3987.98 4614.02,3942 4626.13,3929.89 USB2.14@4648.48,3929.89
  Bottom Layer w5: v2(4575,4135) 4568,4142 4568,4200 4803,4435 5137.73,4435 5284.73,4582 6357.73,4582 6478,4702.27 6478,4904.73 6360.73,5022 6300,5022 6250,5072 6250,5178 6192.94,5235.06 6192.94,5237.56 6195,5239.63 v2(6195,5250)
USB2-RXP: D15.2 D15.9 U14.B23 USB2.15 | length 3314.1
  Top Layer w3: U14.B23@6062.26,5237.36 6064.62,5235 6094.9,5235 6100.12,5229.78 6118.78,5229.78 6134,5245 6165,5245 v2(6176,5256)
  Top Layer w5: v2(4554,4135) 4557,4132 4557,4120 4554.7,4117.7 D15.2@4554.7,4104.33 D15.9@4554.7,4069.67 4554.7,4053.78 4560.03,4048.46 4560.03,4029.22 4605,3984.25 4605,3942 4592.89,3929.89 USB2.15@4569.74,3929.89
  Bottom Layer w5: v2(4554,4135) 4560,4141 4560,4155.37 4555,4160.37 4542,4160.37 4537,4165.37 4537,4170.37 4542,4175.37 4555,4175.37 4560,4180.37 4560,4204.73 4799.27,4444 5134,4444 5281,4591 6354,4591 6469,4706 6469,4901 6357,5013 6296.27,5013 6241,5068.27 6241,5175.69 6176,5240.69 v2(6176,5256)
USB2-TXN: C219.1 U14.B22 | length 3017.1
  Top Layer w3: U14.B22@6062.85,5257.05 ccw(c6093.59,5279.33) 6075.98,5245.69 ccw(c6082.89,5258.9) 6093.43,5248.36 6102.07,5257 6141,5257 6155,5271 v2(6155,5273)
  Top Layer w5: v2(4515,4180) 4510,4175 4510,4169 4515.25,4163.75 C219.1@4515.25,4159.75
  Bottom Layer w5: v2(4515,4180) 4509,4186 4509,4202.27 4777.09,4470.36 5112.36,4470.36 5255,4613 6329.73,4613 6441,4724.27 6441,4894.73 6349.73,4986 6284,4986 6217,5053 6217,5158 6149.5,5225.5 6149.5,5256.13 6155,5261.63 v2(6155,5273)
USB2-TXP: C220.1 U14.A22 | length 3016.5
  Top Layer w3: U14.A22@6081.94,5257.04 6091.04,5257.04 6100,5266 6129,5266 v2(6135,5272)
  Top Layer w5: C220.1@4494.25,4159.75 4499,4164.5 4499,4176 v2(4495,4180)
  Bottom Layer w5: v2(4495,4180) 4500,4185 4500,4206 4508.96,4214.96 4508.96,4225.96 4514.07,4231.07 4525.07,4231.07 4530.17,4236.17 4530.17,4247.17 4535.28,4252.28 4546.28,4252.28 4551.39,4257.39 4551.39,4268.39 4556.49,4273.49 4567.49,4273.49 4572.6,4278.6 4572.6,4289.6 4577.71,4294.71 4588.71,4294.71 4593.81,4299.81 4593.81,4310.81 4598.92,4315.92 4609.92,4315.92 4615.03,4321.03 4615.03,4332.03 4620.13,4337.13 4631.13,4337.13 4636.24,4342.24 4636.24,4353.24 4641.35,4358.35 4652.35,4358.35 4657.45,4363.45 4657.45,4374.45 4662.56,4379.56 4673.56,4379.56 4773.36,4479.36 5108.64,4479.36 5252.27,4623 6327,4623 6432,4728 6432,4891 6346,4977 6280.27,4977 6208,5049.27 6208,5154 6140.5,5221.5 6140.5,5256.13 6135,5261.63 v2(6135,5272)
VBUS: C27.2 C28.2 C221.2 C222.2 C246.2 C247.2 C280.2 C294.2 D1.2 D3.2 D9.2 FPC1.1 FPC1.2 H1.2 H1.4 LED2.4 LED3.4 LED4.4 LED5.4 R52.1 R53.1 U4.49 U4.50 U11.3 U17.5 USB2.1 USB2.10 | length 12204.5
  Top Layer w5: v2(4906,4384) 4912,4390 4992,4390 ; R52.1@4981,4353.51 4981,4379 4992,4390 ; R53.1@5023,4353.51 5023,4379 5012,4390 4992,4390
  Top Layer w6: C222.2@4903.01,4380 C221.2@4903.01,4411.93
  Top Layer w8: D9.2@4906,4310 v2(4906,4336)
  Top Layer w10: LED5.4@3451.16,3782.34 3438.66,3782.34 3415,3806 3415,3862.45 LED4.4@3451.16,3898.6 3443.4,3898.6 3414,3928 3414,3977.7 LED3.4@3451.16,4014.86 3440.14,4014.86 3421,4034 v1(3421,4100.96) LED2.4@3451.16,4131.12
  Top Layer w20: v1(4026,4900) 4026,4840.16 D1.2@4027,4839.16 ; U17.5@7059.88,6092.42 7059.3,6093 C280.2@7103,6093.01 v2(7138,6093) v2(7156,6093)
  内层2 w20: v1(3772,5175) 3772,5153 3962,4963 3963,4963 v1(4026,4900)
  内层4 w20: v1(4850.46,4119.46) v1(4863.35,4132.35) 5002,4271 5322,4271 5369,4318 5607,4318 5687,4398 5743,4398 5787,4442 6027,4442 6061,4408 6227,4408 6296,4339 6445,4339 6532,4426 7122,4426 7191,4357 v1(7191,4336)
  Inner5 w20: v1(3421,4100.96) 3498,4177.96 3498,4212 ; 3593,6213 3593,6277 H1.2@3659,6343 H1.4@3759,6343 ; v2(7156,6093) v2(7138,6093) 7120,6075 7120,5937 7139,5918 7139,5661 7090,5612 7090,5474 7116,5448 7116,5368 7191,5293 v1(7191,4336)
  Inner5 w50: 3446,4968 3446,5492 3432.8,5505.2 3432.8,5613.8 3462,5643 3462,6031.56 ; 3453.97,4964.14 3474,4945 ; 3461,6038 3462,6037 3462,6031.56 ; 3593,6213 3593,6162.56 3462,6031.56 ; v1(3639,4934) 3639,5005 3680,5046 ; v1(3772,5175) v1(3772,5155) 3772,5140 3773,5139 3680,5046 ; 4210,4047 4242,4079 4757,4079 4784,4052 ; 4218,4041 4080,4041 4036,3997 3604,3997 3511,4090 3511,4217 3474,4254 3474,4945 ; 3474,4945 3575,5046 3680,5046
  Bottom Layer w8: v2(4906,4336) v2(4906,4384)
  Bottom Layer w10: FPC1.2@3564.97,4927.6 3632.59,4927.6 v1(3639,4934) ; FPC1.1@3564.97,4947.28 3625.72,4947.28 v1(3639,4934) ; C247.2@3638.99,4955 v1(3639,4934)
  Bottom Layer w20: v1(3772,5155) v1(3772,5175) ; USB2.1@4353.22,3744.85 4372,3763.64 4372,3852.04 USB2.10@4353.22,3870.83 ; v1(4774.95,4043.95) 4783.15,4052.15 v1(4790.82,4059.82) v1(4850.46,4119.46) ; v1(4863.35,4132.35) 4906,4175 v2(4906,4336) ; C246.2@7184.99,4455.28 7189,4451.28 U11.3@7189,4392.61 7191,4390.61 v1(7191,4336)
  Bottom Layer w50: USB2.1@4353.22,3744.85 4353.21,3668.79 4487,3535 4789,3535 4850,3596 4850,3985.3 4783.15,4052.15 C294.2@4779,4056.3
  other v1: 4804,4037 4761,4071 3530,5441
  other v2: 3510.2,5375.6 3510.2,5398.17 3510.2,5419.14 3510.2,5440 3550,5443
VBUS-USB: C281.2 C282.2 R120.2 U17.1 USB3.A4B9 USB3.B4A9 | length 539.1
  Top Layer w6: U17.1@6969.04,6092.42 6969.04,6141.53 R120.2@6973.23,6145.72
  Top Layer w20: USB3.B4A9@6623.54,6158.7 6623.54,6193.54 6636,6206 6679,6206 6690,6217 6733,6217 6747,6203 6801,6203 6816.46,6187.54 USB3.A4B9@6816.46,6158.7 6816.46,6129.54 6855.31,6090.69 C282.2@6855.31,6085.73 C281.2@6907.77,6085.73 6914.47,6092.42 U17.1@6969.04,6092.42
VCC-3V3-BLK: C277.2 R126.2 U16.1 | length 82.2
  Bottom Layer w10: U16.1@6840.91,5340.31 6841,5340.21 R126.2@6841,5286 6843.01,5284 C277.2@6868,5284
VCC-LDO-RTC: C45.2 C92.2 R9.1 R10.1 U4.35 U14.AE13 | length 2853.2
  Top Layer w6: R9.1@3595,5329.49 v2(3595,5314) 3600,5309 3643,5309 3657,5323 R10.1@3657,5328.49
  Top Layer w8: C45.2@3557,5661 3559,5661 3575,5645 3644,5645 3657.62,5631.38 U4.35@3657.62,5615.33 ; U14.AE13@5609.5,5434.21 5609.5,5435.5 v1(5629,5455)
  内层2 w6: v2(3595,5314) 3595,5433 v1(3600,5438)
  Inner5 w15: v1(3563.49,5656.51) 3606,5614 3837,5614 3842,5609 3883,5609 3908,5584 v1(3920,5584)
  Bottom Layer w6: v1(3563.49,5656.51) 3577,5643 3619,5643 3625,5637 3625,5463 v1(3600,5438)
  Bottom Layer w8: v1(3920,5584) 3981,5645 5210,5645 5377.62,5477.38 5606.62,5477.38 v1(5629,5455)
VCM-ADC: C112.2 U14.Y9 | length 24.2
  Bottom Layer w8: C112.2@5698,5533 5699,5532 5699,5525 5707.92,5516.08 v1(5707.92,5512.95)
VDD-CPUBFB: U5.1 U5.16 U14.R22 | length 2793.8
  Top Layer w8: U5.1@4019.34,5208.9 4029.44,5219 v2(4032,5219) ; v2(4043,5108) 4043.25,5108.25 U5.16@4043.25,5121.99
  内层2 w10: v2(4032,5219) 4080,5219 4415,5554 4415,5668 4604,5857 5418,5857 5538,5737 5538,5723 5575,5686 5599,5686 5703,5582 5745,5582 5761,5566 5761,5532 5785,5508 5787,5508 5787,5481 5769,5463 5769,5443 5778,5434 5801,5434 5843,5392 5843,5330 5868,5305 5868,5284 5841.04,5257.04 v1(5806.35,5257.04)
  Bottom Layer w10: v2(4032,5219) 4049,5219 4067,5201 4067,5172 4043,5148 v2(4043,5108)
VDD-CPULFB: U4.12 U14.AA19 | length 2440.1
  Top Layer w10: U4.12@3767.85,5385.61 3767.85,5362.15 v2(3769,5361)
  Inner5 w10: v2(3769,5361) 3757,5349 3757,5265 3796,5226 3884,5226 4054,5396 4356,5396 4630,5670 5169,5670 5365,5474 5388,5474 5399,5463 5399,5440 5422,5417 5459,5417 5480,5396 5616,5396 5629,5383 5648,5383 5665,5366 5665,5327 5676,5316 v1(5688,5316)
VDD-DNRFB: U5.4 U14.AB13 | length 2072
  Top Layer w8: v1(3952,5268) 3957,5268 3964,5261 3964,5232 3972.09,5223.91 U5.4@3972.09,5208.9
  VCC w10: v1(3952,5268) 3970,5286 4230,5286 4603,5659 5153,5659 5414,5398 5632.34,5398 v1(5668.55,5434.21)
VDD-SYSFB: U4.34 U14.P18 | length 2590.2
  Top Layer w8: v2(3665,5592) 3673.36,5600.36 U4.34@3673.36,5615.33
  Top Layer w10: U14.P18@5826.04,5335.78 v1(5826,5356)
  内层4 w10: v2(3665,5592) 3665,5665 3706,5706 3706,5755 3775,5824 3897,5824 3921,5800 4012,5800 4138,5674 5138,5674 5417,5395 5661,5395 5721,5335 5810.85,5335 5826,5350.15 v1(5826,5356)
VRA1: C109.2 U14.AG5 | length 39.6
  Top Layer w6: U14.AG5@5570.13,5591.69 v2(5589.13,5591.69)
  Bottom Layer w6: v2(5589.13,5591.69) 5606.31,5591.69 C109.2@5608.75,5589.25
VRA2: C110.2 U14.AG4 | length 38.7
  Top Layer w6: U14.AG4@5570.13,5611.38 v2(5589.13,5611.38)
  Bottom Layer w6: v2(5589.13,5611.38) 5608.62,5611.38 C110.2@5608.75,5611.25
VREFP-ADC: C113.2 R24.1 U14.AA9 | length 50.7
  Bottom Layer w4: R24.1@5685.49,5491 5685.49,5510.2 v2(5688.24,5512.95)
  Bottom Layer w8: C113.2@5670,5533 5688.24,5514.76 v2(5688.24,5512.95)
VRP: C111.2 U14.AC7 | length 38
  Bottom Layer w7: v2(5648.87,5552.32) 5652,5555.45 C111.2@5652,5589
WL-REG-ON: U9.12 U14.U2 | length 2177.4
  Top Layer w3: U14.U2@5766.89,5650.71 5766.89,5654.97 5776.48,5664.56 5776.48,5675.46 5770.04,5681.9 5769.81,5688.24 5766.57,5702.15 5764.83,5716.51 5765.87,5731.57 5769.46,5739.8
  Top Layer w4: U9.12@4019.84,5615.94 4029,5606.78 4029,5584 v2(4036,5577) ; v2(4074,5577) 4095,5577 4166,5506 4438,5506 4716,5784 5498,5784 5567,5853 5765,5853 5791,5827 5791,5767 5779,5755 5769.17,5738.87
  Bottom Layer w4: v2(4036,5577) v2(4074,5577)
WL-WAKE-AP: U9.13 U14.U1 | length 2113
  Top Layer w3: U14.U1@5766.89,5670.41 5766.78,5670.41 5764,5673.19 5763.47,5683.14 5756.75,5697.86 5755.01,5717.79 5757.09,5735.86 5767.75,5757.64
  Top Layer w4: U9.13@4055.27,5615.94 4055.27,5572.73 4067,5561 4090,5561 4157,5494 4447,5494 4725,5772 5503,5772 5572,5841 5758,5841 5780,5819 5780,5769 5768,5757
X32KIN: C100.2 R25.1 U14.AM12 X2.1 | length 311.7
  Top Layer w4: X2.1@5298.45,5532.12 5332.36,5532.12 5342.56,5542.32 C100.2@5352.45,5542.32 ; C100.2@5353.45,5541.32 C100.2@5352.45,5542.32 ; U14.AM12@5471.7,5453.91 5405.85,5453.91 5380,5479.76 5380,5566.76 5370,5576.76 5358.4,5576.76 R25.1@5352.45,5570.81 C100.2@5352.45,5542.32
X32KOUT: C101.2 R25.2 U14.AM11 X2.2 | length 316.6
  Top Layer w4: X2.2@5298.45,5632.52 5330.24,5632.52 5340.94,5621.82 C101.2@5352.45,5621.82 R25.2@5352.45,5589.83 5356.52,5585.76 5372,5585.76 5389,5568.76 5389,5483.76 5410,5462.76 5460.88,5462.76 U14.AM11@5471.7,5473.58
"": D12.5 D12.6 D13.1 D13.2 D13.9 D13.10 D14.1 D14.2 D14.9 D14.10 DC1.4 FAN.1 FAN.2 FPC1.34 FPC1.45 FPC1.46 FPC1.47 FPC1.48 FPC1.49 FPC2.1 LED5.1 TFT1.1 TFT1.2 TFT1.9 U4.2 U4.3 U4.4 U4.5 U4.36 U4.40 U5.10 U8.A1 U8.A2 U8.A7 U8.A8 U8.A9 U8.A10 U8.A11 U8.A12 U8.A13 U8.A14 U8.B1 U8.B7 U8.B8 U8.B9 U8.B10 U8.B11 U8.B12 U8.B13 U8.B14 U8.C1 U8.C3 U8.C5 U8.C7 U8.C8 U8.C9 U8.C10 U8.C11 U8.C12 U8.C13 U8.C14 U8.D1 U8.D2 U8.D3 U8.D4 U8.D12 U8.D13 U8.D14 U8.E1 U8.E2 U8.E3 U8.E5 U8.E8 U8.E9 U8.E10 U8.E12 U8.E13 U8.E14 U8.F1 U8.F2 U8.F3 U8.F10 U8.F12 U8.F13 U8.F14 U8.G1 U8.G2 U8.G3 U8.G10 U8.G12 U8.G13 U8.G14 U8.H1 U8.H2 U8.H3 U8.H12 U8.H13 U8.H14 U8.J1 U8.J2 U8.J3 U8.J12 U8.J13 U8.J14 U8.K1 U8.K2 U8.K3 U8.K6 U8.K7 U8.K10 U8.K12 U8.K13 U8.K14 U8.L1 U8.L2 U8.L3 U8.L12 U8.L13 U8.L14 U8.M1 U8.M2 U8.M3 U8.M7 U8.M8 U8.M9 U8.M10 U8.M11 U8.M12 U8.M13 U8.M14 U8.N1 U8.N3 U8.N6 U8.N7 U8.N8 U8.N9 U8.N10 U8.N11 U8.N12 U8.N13 U8.N14 U8.P1 U8.P2 U8.P7 U8.P8 U8.P9 U8.P10 U8.P11 U8.P12 U8.P13 U8.P14 U9.4 U9.5 U9.8 U9.10 U9.11 U9.21 U9.23 U9.24 U9.25 U9.26 U9.27 U9.28 U9.29 U9.30 U9.32 U9.35 U9.37 U9.38 U9.39 U9.40 U14.A5 U14.A8 U14.A16 U14.AA1 U14.AA2 U14.AA3 U14.AA4 U14.AA5 U14.AA6 U14.AB2 U14.AB3 U14.AC2 U14.AC3 U14.AC4 U14.AC5 U14.AC6 U14.AD1 U14.AD2 U14.AE1 U14.AE2 U14.AE4 U14.AE5 U14.AE6 U14.AG1 U14.AG2 U14.AG13 U14.AG17 U14.AH1 U14.AH2 U14.AH11 U14.AH13 U14.AH15 U14.AJ1 U14.AJ15 U14.AK1 U14.AK13 U14.AK15 U14.AK33 U14.AL5 U14.AL7 U14.AL11 U14.AL15 U14.AL27 U14.AL32 U14.AL33 U14.AM6 U14.AM7 U14.AM8 U14.AM14 U14.AM15 U14.AM16 U14.AM17 U14.AM18 U14.AM33 U14.AN4 U14.AN7 U14.AN8 U14.AN15 U14.AN17 U14.AN26 U14.B6 U14.B7 U14.B8 U14.B9 U14.B15 U14.C7 U14.C9 U14.C15 U14.F20 U14.G4 U14.G16 U14.J2 U14.M3 U14.N1 U14.N4 U14.N5 U14.N31 U14.N32 U14.N33 U14.U28 U14.U29 U14.U30 U14.U33 U14.W4 U14.W5 U14.W6 U14.W29 U14.Y2 U14.Y3 UD1.A1 UD1.A2 UD1.A11 UD1.A12 UD1.AA1 UD1.AA12 UD1.AB1 UD1.AB2 UD1.AB11 UD1.AB12 UD1.B1 UD1.B12 UD1.G11 UD1.K5 UD1.K8 UD1.N5 UD1.N8 USB2.5 USB2.6 USB2.8 USB2.9
  other v4: 3825.32,4760.31 3864.68,4760.31 3825.32,4799.69 3864.68,4799.69 5750.32,5974.31 5789.69,5974.31 5750.32,6013.68 5789.69,6013.68

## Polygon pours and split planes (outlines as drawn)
GND on Top Layer (solid, remove dead copper, pour order 8): 3000,3061 7558,3061 7558,6661 3000,6661
GND on 内层2 (solid, remove dead copper, pour order 9): 3033.54,3040 7591.54,3040 7591.54,6640 3033.54,6640
GND on GND1 (solid, remove dead copper, pour order 10): 3026.2,3052 7584.2,3052 7584.2,6652 3026.2,6652
GND on VCC (solid, remove dead copper, pour order 12): 3039,3034 7597,3034 7597,6634 3039,6634
GND on 内层4 (solid, remove dead copper, pour order 16): 3047,3025 7605,3025 7605,6625 3047,6625
GND on Inner5 (solid, remove dead copper, pour order 17): 3053.47,3017.38 7611.47,3017.38 7611.47,6617.38 3053.47,6617.38
GND on GND2 (solid, remove dead copper, pour order 18): 3061,3010 7619,3010 7619,6610 3061,6610
GND on Bottom Layer (solid, remove dead copper, pour order 19): 3071,3000 7629,3000 7629,6600 3071,6600
GND on GND1 (solid, remove dead copper, pour order 0): 5730.92,5249.97 5674.92,5249.97 5662.92,5261.97 5662.92,5357.97 5630.92,5389.97 5387.92,5389.97 5133.92,5643.97 4624.92,5643.97 4604.92,5623.97 4604.92,5014.97 4720.92,4898.97 5676.92,4898.97 5741.92,4963.97 5741.92,5238.97
GND on GND2 (solid, remove dead copper, pour order 1): 5730.44,5250.47 5674.44,5250.47 5662.44,5262.47 5662.44,5358.47 5630.44,5390.47 5387.44,5390.47 5133.44,5644.47 4624.44,5644.47 4604.44,5624.47 4604.44,5015.47 4720.44,4899.47 5676.44,4899.47 5741.44,4964.47 5741.44,5239.47
GND on GND1 (solid, remove dead copper, pour order 2): 5730.86,5251.03 5674.86,5251.03 5662.86,5263.03 5662.86,5359.03 5630.86,5391.03 5387.86,5391.03 5133.86,5645.03 4624.86,5645.03 4604.86,5625.03 4604.86,5016.03 4720.86,4900.03 5676.86,4900.03 5741.86,4965.03 5741.86,5240.03
GND on VCC (solid, remove dead copper, pour order 3): 5731.42,5250.47 5675.42,5250.47 5663.42,5262.47 5663.42,5358.47 5631.42,5390.47 5388.42,5390.47 5134.42,5644.47 4625.42,5644.47 4605.42,5624.47 4605.42,5015.47 4721.42,4899.47 5677.42,4899.47 5742.42,4964.47 5742.42,5239.47
DCDC3 on 内层4 (solid, remove dead copper, pour order 4): 5730.74,5249.47 5674.74,5249.47 5662.74,5261.47 5662.74,5357.47 5642.74,5377.47 5392.74,5377.47 5128.74,5641.47 4622.74,5641.47 4604.74,5623.47 4604.74,5014.47 4720.74,4898.47 5676.74,4898.47 5741.74,4963.47 5741.74,5238.47
BLDO2 on Bottom Layer (solid, remove dead copper, pour order 5): 5049.92,4994.97 5106.39,5051.44 5106.39,5582.5 5052.92,5635.97 4660.4,5635.97 4608.65,5584.22 4608.65,5040.29 4653.97,4994.97
323-DCDC1/2 on 内层2 (solid, remove dead copper, pour order 6): 5683.92,5366.51 5683.92,5263.51 5708.43,5239 5802,5239 5816,5253 5816,5444.25 5416.25,5844 4614,5844 4419,5649 4419,5534 4155,5270 4155,5083 4205,5033 4262,5033 4345,5116 4345,5220 4579,5454 4579,5597 4644,5662 5223,5662 5497,5388 5662.43,5388
PS on 内层2 (solid, remove dead copper, pour order 7): 3612.01,5664.28 3860.35,5664.28 3929,5595.63 3929,5393 4106,5216 4106,5080 4074,5048 3946,5048 3750,5244 3553,5244 3472,5325 3472,5611.07 3514.47,5653.53 3601.26,5653.53
323-DCDC3 on VCC (solid, remove dead copper, pour order 11): 5742,5464 5742,5425 5722,5405 5612,5405 5611,5406 5404,5406 5152,5658 4598,5658 4222.71,5282.71 4057.84,5282.71 4006,5334.55 4006,5395 4095,5484 4203,5484 4545,5826 5223.83,5826 5536.88,5512.95 5693.05,5512.95
DCDC3 on 内层4 (solid, remove dead copper, pour order 13): 3756.57,5739 3756.57,5637.28 3774.85,5619 3854,5619 3936,5537 3936,5502 4041.03,5396.97 4616.92,5396.97 4685.67,5465.72 4685.67,5641 4119,5641 4000,5760 3909,5760 3877,5792 3809.57,5792
DCDC2 on 内层4 (solid, remove dead copper, pour order 14): 5652,5411.39 5652,5413 5397,5413 5141,5669 4135,5669 4010,5794 3919,5794 3894,5819 3759,5819 3711,5771 3711,5725 3694,5708 3585,5708 3559,5734 3559,5840 3650,5931 4152.51,5931 4246.51,5837 5477,5837 5916,5398 5939,5398 5951,5386 5951,5350 5857,5256 5832,5256 5821,5267 5800,5267 5790,5277 5790,5318.66 5779.9,5328.76 5734.63,5328.76
DCDC1 on Inner5 (solid, remove dead copper, pour order 15): 5756,5331 5756,5280 5740,5264 5700.96,5264 5668,5296.96 5668,5350.19 5605.6,5412.59 5419.41,5412.59 5167,5665 4632,5665 4360,5393 4056,5393 3883,5220 3793.26,5220 3749.26,5264 3749.26,5369.09 3941.17,5561 4218,5561 4523,5866 5144,5866 5254,5756 5396.65,5756 5755,5397.65 5755,5332
GND on Bottom Layer (solid, remove dead copper, pour order 20): 5927,6146 5927,6139 5929,6137 5929,6135 5932,6132 5932,6141

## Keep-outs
Top Layer:
  region net "": 5201.92,5525.98 5171.93,5555.97 5128.92,5555.97 5050.92,5633.97 4654.92,5633.97 4638.92,5617.97 4638.92,5011.97 4677.92,4972.97 5400.91,4972.97 5409.16,4964.72 5685.67,4964.72 5711.92,4990.97 5711.92,5181.37 5704.57,5188.72 5600.17,5188.72 5585.92,5202.97 5585.92,5316.97 5576.92,5325.97 5471.92,5325.97 5467.92,5329.97 5422.92,5329.97 5379.92,5372.97 5243.55,5372.97 5202,5414.52 5202,5423 5201.92,5423.08
内层2:
  region net "": 5654.37,4988.43 5582.92,4916.97 4975.08,4916.97 4876.58,5015.47 4639.36,5015.47 4637.1,5017.73 4637.1,5604.71 4658.36,5625.97 5158.92,5625.97 5392.92,5391.97 5424.92,5391.97 5506.92,5309.97 5594.92,5309.97 5654.37,5250.52
Inner5:
  region net "": 5727.92,5157.93 5707.6,5178.25 5505.35,5178.25 5489.62,5193.97 5489.62,5235.24 5497.86,5243.47 5557.76,5243.47 5586.92,5272.63 5586.92,5305.97 5543.63,5349.26 5530.44,5349.26 5491.73,5387.97 5393.92,5387.97 5141.92,5639.97 4647.04,5639.97 4608.29,5601.22 4608.29,5497.35 4605.92,5494.97 4605.92,5057.97 4745.92,4917.97 5671.37,4917.97 5727.92,4974.52
Board Outline Layer:
  lines w10 net "": 3348,3578.11 ccw(c3466.11,3578.11) 3466.11,3460 7166.9,3460 ccw(c7166.9,3578.11) 7285.01,3578.11 7285.01,6294.65 ccw(c7166.9,6294.65) 7166.9,6412.76 3466.11,6412.76 ccw(c3466.11,6294.65) 3348,6294.65 3348,3578.11
Multi-Layer:
  region net "": 5863.7,4256.39 6076.3,4256.39 6193.53,4139.16 6308,4139.16 6308,3458.89 5678.11,3458.89 5678,3459 5678,4139.16 5746.47,4139.16
  region net "": 6581.95,4255.69 6794.55,4255.69 6911.78,4138.46 7026.25,4138.46 7026.25,3458.19 6396.36,3458.19 6396.25,3458.31 6396.25,4138.46 6464.72,4138.46

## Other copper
Top Layer:
  drawing of 1835 lines, arcs and shapes, not listed
内层2:
  drawing of 217 lines, arcs and shapes, not listed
